VERSION 5.8 ;
BUSBITCHARS "[]" ;
DIVIDERCHAR "/" ;

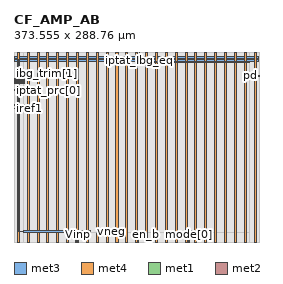
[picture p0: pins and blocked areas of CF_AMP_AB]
MACRO CF_AMP_AB
  CLASS BLOCK ;
  ORIGIN 0 0 ;
  FOREIGN CF_AMP_AB 0 0 ;
  SIZE 373.555 BY 288.76 ;
  PIN vpwrlv
    DIRECTION INPUT ;
    USE SIGNAL ;
    PORT
      LAYER met3 ;
        RECT 191.97 271.02 193.47 273.76 ;
        RECT 194.265 270.825 195.395 273.76 ;
        RECT 192.48 270.825 195.07 273.76 ;
    END
  END vpwrlv
  PIN vgnd
    DIRECTION INPUT ;
    USE GROUND ;
    PORT
      LAYER met3 ;
        RECT 15 15 116.115 17.065 ;
        RECT 7.26 15.795 15 16.275 ;
        RECT 7.26 15.795 7.74 277.36 ;
        RECT 1.23 274.26 372.325 277.36 ;
      LAYER met4 ;
        RECT 20 0 23.1 288.76 ;
        RECT 50 0 53.1 288.76 ;
        RECT 80 0 83.1 288.76 ;
        RECT 110 0 113.1 288.76 ;
        RECT 140 0 143.1 288.76 ;
        RECT 170 0 173.1 288.76 ;
        RECT 200 0 203.1 288.76 ;
        RECT 230 0 233.1 288.76 ;
        RECT 260 0 263.1 288.76 ;
        RECT 290 0 293.1 288.76 ;
        RECT 320 0 323.1 288.76 ;
        RECT 350 0 353.1 288.76 ;
    END
  END vgnd
  PIN vpwr
    DIRECTION INPUT ;
    USE POWER ;
    PORT
      LAYER met3 ;
        RECT 196.75 272.955 357.825 273.76 ;
        RECT 1.23 279.06 372.325 282.16 ;
      LAYER met4 ;
        RECT 5 0 8.1 288.76 ;
        RECT 35 0 38.1 288.76 ;
        RECT 65 0 68.1 288.76 ;
        RECT 95 0 98.1 288.76 ;
        RECT 125 0 128.1 288.76 ;
        RECT 155 0 158.1 288.76 ;
        RECT 185 0 188.1 288.76 ;
        RECT 215 0 218.1 288.76 ;
        RECT 245 0 248.1 288.76 ;
        RECT 275 0 278.1 288.76 ;
        RECT 305 0 308.1 288.76 ;
        RECT 335 0 338.1 288.76 ;
        RECT 365 0 368.1 288.76 ;
    END
  END vpwr
  PIN vneg
    DIRECTION INOUT ;
    USE SIGNAL ;
    PORT
      LAYER met3 ;
        RECT 145.48 15 151.175 17.385 ;
    END
  END vneg
  PIN vout
    DIRECTION OUTPUT ;
    USE SIGNAL ;
    PORT
      LAYER met3 ;
        RECT 270.26 15 272.5 17.515 ;
    END
  END vout
  PIN phi_1b
    DIRECTION INPUT ;
    USE SIGNAL ;
    PORT
      LAYER met1 ;
        RECT 94.415 0 94.675 16.055 ;
    END
  END phi_1b
  PIN phi_1
    DIRECTION INPUT ;
    USE SIGNAL ;
    PORT
      LAYER met1 ;
        RECT 93.955 0 94.215 16.045 ;
    END
  END phi_1
  PIN pd
    DIRECTION INPUT ;
    USE SIGNAL ;
    PORT
      LAYER met2 ;
        RECT 357.755 252.29 373.555 252.55 ;
    END
  END pd
  PIN mode[1]
    DIRECTION INPUT ;
    USE SIGNAL ;
    PORT
      LAYER met1 ;
        RECT 265.83 0 266.06 16.02 ;
    END
  END mode[1]
  PIN mode[0]
    DIRECTION INPUT ;
    USE SIGNAL ;
    PORT
      LAYER met1 ;
        RECT 266.26 0 266.49 16.01 ;
    END
  END mode[0]
  PIN iref2
    DIRECTION INPUT ;
    USE SIGNAL ;
    PORT
      LAYER met2 ;
        RECT 0 207.795 15.95 208.44 ;
    END
  END iref2
  PIN iref1
    DIRECTION INPUT ;
    USE SIGNAL ;
    PORT
      LAYER met2 ;
        RECT 0 202.365 16.01 203.005 ;
    END
  END iref1
  PIN in_sel
    DIRECTION INPUT ;
    USE SIGNAL ;
    PORT
      LAYER met1 ;
        RECT 188.685 0 188.945 15.89 ;
    END
  END in_sel
  PIN enable_hv
    DIRECTION INPUT ;
    USE SIGNAL ;
    PORT
      LAYER met2 ;
        RECT 356.735 251.83 373.555 252.09 ;
    END
  END enable_hv
  PIN Vinp
    DIRECTION INPUT ;
    USE SIGNAL ;
    PORT
      LAYER met1 ;
        RECT 96.715 0 96.975 15.605 ;
    END
  END Vinp
  PIN Vinn
    DIRECTION INPUT ;
    USE SIGNAL ;
    PORT
      LAYER met1 ;
        RECT 97.635 0 97.895 15.645 ;
    END
  END Vinn
  PIN iptat_Ibg_eq
    DIRECTION INPUT ;
    USE SIGNAL ;
    PORT
      LAYER met2 ;
        RECT 190.19 273.375 190.39 288.76 ;
    END
  END iptat_Ibg_eq
  PIN iptat
    DIRECTION INPUT ;
    USE SIGNAL ;
    PORT
      LAYER met2 ;
        RECT 0 240.48 15.525 240.655 ;
    END
  END iptat
  PIN iptat_prc[2]
    DIRECTION INPUT ;
    USE SIGNAL ;
    PORT
      LAYER met2 ;
        RECT 0 232.145 16.16 232.32 ;
    END
  END iptat_prc[2]
  PIN iptat_prc[0]
    DIRECTION INPUT ;
    USE SIGNAL ;
    PORT
      LAYER met2 ;
        RECT 0 230.455 16.16 230.595 ;
    END
  END iptat_prc[0]
  PIN iptat_prc[1]
    DIRECTION INPUT ;
    USE SIGNAL ;
    PORT
      LAYER met2 ;
        RECT 0 231.665 16.16 231.805 ;
    END
  END iptat_prc[1]
  PIN iptat_prc[3]
    DIRECTION INPUT ;
    USE SIGNAL ;
    PORT
      LAYER met2 ;
        RECT 0 231.085 16.16 231.225 ;
    END
  END iptat_prc[3]
  PIN iptat_prc[4]
    DIRECTION INPUT ;
    USE SIGNAL ;
    PORT
      LAYER met2 ;
        RECT 0 230.035 16.16 230.175 ;
    END
  END iptat_prc[4]
  PIN ibg_trim[6]
    DIRECTION INPUT ;
    USE SIGNAL ;
    PORT
      LAYER met2 ;
        RECT 0 242.28 16.495 242.44 ;
    END
  END ibg_trim[6]
  PIN iptat_trim[0]
    DIRECTION INPUT ;
    USE SIGNAL ;
    PORT
      LAYER met2 ;
        RECT 0 246.37 16.305 246.57 ;
    END
  END iptat_trim[0]
  PIN iptat_trim[1]
    DIRECTION INPUT ;
    USE SIGNAL ;
    PORT
      LAYER met2 ;
        RECT 0 246.77 16.305 246.97 ;
    END
  END iptat_trim[1]
  PIN iptat_trim[2]
    DIRECTION INPUT ;
    USE SIGNAL ;
    PORT
      LAYER met2 ;
        RECT 0 247.17 16.31 247.37 ;
    END
  END iptat_trim[2]
  PIN iptat_trim[3]
    DIRECTION INPUT ;
    USE SIGNAL ;
    PORT
      LAYER met2 ;
        RECT 0 247.57 16.305 247.77 ;
    END
  END iptat_trim[3]
  PIN iptat_trim[4]
    DIRECTION INPUT ;
    USE SIGNAL ;
    PORT
      LAYER met2 ;
        RECT 0 245.57 16.305 245.77 ;
    END
  END iptat_trim[4]
  PIN ibg_trim[0]
    DIRECTION INPUT ;
    USE SIGNAL ;
    PORT
      LAYER met2 ;
        RECT 0 245.97 16.5 246.17 ;
    END
  END ibg_trim[0]
  PIN ibg_trim[1]
    DIRECTION INPUT ;
    USE SIGNAL ;
    PORT
      LAYER met2 ;
        RECT 0 244.63 16.23 244.79 ;
    END
  END ibg_trim[1]
  PIN ibg_trim[2]
    DIRECTION INPUT ;
    USE SIGNAL ;
    PORT
      LAYER met2 ;
        RECT 0 244.085 16.49 244.245 ;
    END
  END ibg_trim[2]
  PIN ibg_trim[3]
    DIRECTION INPUT ;
    USE SIGNAL ;
    PORT
      LAYER met2 ;
        RECT 0 243.635 16.495 243.795 ;
    END
  END ibg_trim[3]
  PIN ibg_trim[4]
    DIRECTION INPUT ;
    USE SIGNAL ;
    PORT
      LAYER met2 ;
        RECT 0 243.17 16.495 243.33 ;
    END
  END ibg_trim[4]
  PIN ibg_trim[5]
    DIRECTION INPUT ;
    USE SIGNAL ;
    PORT
      LAYER met2 ;
        RECT 0 242.69 16.495 242.85 ;
    END
  END ibg_trim[5]
  PIN en_b
    DIRECTION INPUT ;
    USE SIGNAL ;
    PORT
      LAYER met1 ;
        RECT 200.005 0 200.205 15.84 ;
    END
  END en_b
  OBS
    LAYER li1 ;
      RECT 0 0 373.555 288.76 ;
    LAYER met1 ;
      RECT 0 0 15 288.76 ;
      RECT 358.555 0 373.555 288.76 ;
      RECT 15 0 93.955 15 ;
      RECT 94.215 0 94.415 15 ;
      RECT 94.675 0 96.715 15 ;
      RECT 96.975 0 97.635 15 ;
      RECT 97.895 0 188.685 15 ;
      RECT 188.945 0 200.005 15 ;
      RECT 200.205 0 265.83 15 ;
      RECT 266.06 0 266.26 15 ;
      RECT 266.49 0 358.555 15 ;
      RECT 15 273.76 358.555 288.76 ;
    LAYER met2 ;
      RECT 0 0 15 202.365 ;
      RECT 0 203.005 15 207.795 ;
      RECT 0 208.44 15 230.035 ;
      RECT 0 230.175 15 230.455 ;
      RECT 0 230.595 15 231.085 ;
      RECT 0 231.225 15 231.665 ;
      RECT 0 231.805 15 232.145 ;
      RECT 0 232.32 15 240.48 ;
      RECT 0 240.655 15 242.28 ;
      RECT 0 242.44 15 242.69 ;
      RECT 0 242.85 15 243.17 ;
      RECT 0 243.33 15 243.635 ;
      RECT 0 243.795 15 244.085 ;
      RECT 0 244.245 15 244.63 ;
      RECT 0 244.79 15 245.57 ;
      RECT 0 245.77 15 245.97 ;
      RECT 0 246.17 15 246.37 ;
      RECT 0 246.57 15 246.77 ;
      RECT 0 246.97 15 247.17 ;
      RECT 0 247.37 15 247.57 ;
      RECT 0 247.77 15 288.76 ;
      RECT 358.555 0 373.555 251.83 ;
      RECT 358.555 252.09 373.555 252.29 ;
      RECT 358.555 252.55 373.555 288.76 ;
      RECT 15 0 358.555 15 ;
      RECT 15 273.76 190.19 288.76 ;
      RECT 190.39 273.76 358.555 288.76 ;
  END
END CF_AMP_AB

END LIBRARY
